VERSION 5.8 ;
BUSBITCHARS "[]" ;
DIVIDERCHAR "/" ;

# Macros-only LEF, layered on the tech that sequnmap_basic.lef creates.
# Load with loadLibaryLef(tech, ...) AFTER the basic pair; LAYER met1 and
# SITE core come from that tech.

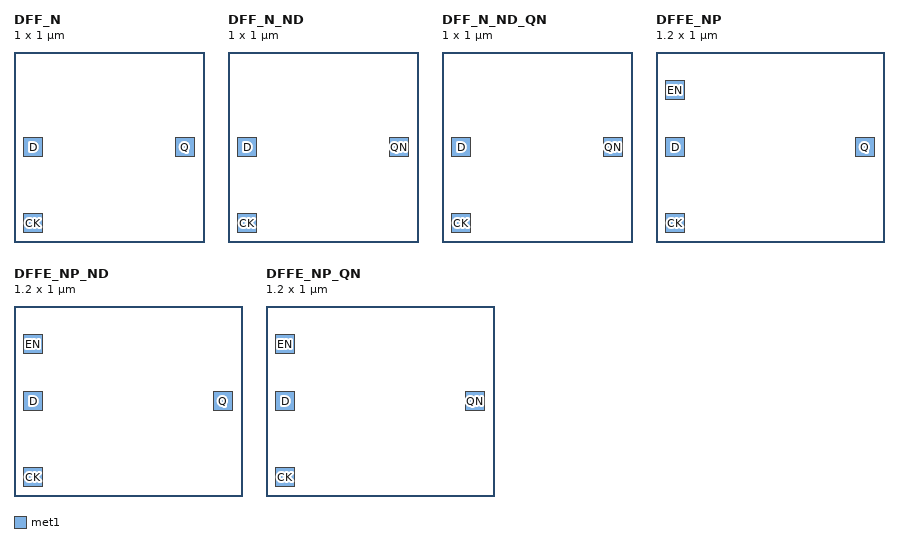
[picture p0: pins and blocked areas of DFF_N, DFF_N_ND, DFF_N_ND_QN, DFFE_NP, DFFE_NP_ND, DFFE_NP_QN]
MACRO DFF_N
  CLASS CORE ;
  ORIGIN 0 0 ;
  SIZE 1.0 BY 1.0 ;
  SITE core ;
  PIN D
    DIRECTION INPUT ;
    USE SIGNAL ;
    PORT
      LAYER met1 ;
      RECT 0.05 0.45 0.15 0.55 ;
    END
  END D
  PIN CK
    DIRECTION INPUT ;
    USE CLOCK ;
    PORT
      LAYER met1 ;
      RECT 0.05 0.05 0.15 0.15 ;
    END
  END CK
  PIN Q
    DIRECTION OUTPUT ;
    USE SIGNAL ;
    PORT
      LAYER met1 ;
      RECT 0.85 0.45 0.95 0.55 ;
    END
  END Q
END DFF_N

MACRO DFF_N_ND
  CLASS CORE ;
  ORIGIN 0 0 ;
  SIZE 1.0 BY 1.0 ;
  SITE core ;
  PIN D
    DIRECTION INPUT ;
    USE SIGNAL ;
    PORT
      LAYER met1 ;
      RECT 0.05 0.45 0.15 0.55 ;
    END
  END D
  PIN CK
    DIRECTION INPUT ;
    USE CLOCK ;
    PORT
      LAYER met1 ;
      RECT 0.05 0.05 0.15 0.15 ;
    END
  END CK
  PIN QN
    DIRECTION OUTPUT ;
    USE SIGNAL ;
    PORT
      LAYER met1 ;
      RECT 0.85 0.45 0.95 0.55 ;
    END
  END QN
END DFF_N_ND

MACRO DFF_N_ND_QN
  CLASS CORE ;
  ORIGIN 0 0 ;
  SIZE 1.0 BY 1.0 ;
  SITE core ;
  PIN D
    DIRECTION INPUT ;
    USE SIGNAL ;
    PORT
      LAYER met1 ;
      RECT 0.05 0.45 0.15 0.55 ;
    END
  END D
  PIN CK
    DIRECTION INPUT ;
    USE CLOCK ;
    PORT
      LAYER met1 ;
      RECT 0.05 0.05 0.15 0.15 ;
    END
  END CK
  PIN QN
    DIRECTION OUTPUT ;
    USE SIGNAL ;
    PORT
      LAYER met1 ;
      RECT 0.85 0.45 0.95 0.55 ;
    END
  END QN
END DFF_N_ND_QN

MACRO DFFE_NP
  CLASS CORE ;
  ORIGIN 0 0 ;
  SIZE 1.2 BY 1.0 ;
  SITE core ;
  PIN D
    DIRECTION INPUT ;
    USE SIGNAL ;
    PORT
      LAYER met1 ;
      RECT 0.05 0.45 0.15 0.55 ;
    END
  END D
  PIN EN
    DIRECTION INPUT ;
    USE SIGNAL ;
    PORT
      LAYER met1 ;
      RECT 0.05 0.75 0.15 0.85 ;
    END
  END EN
  PIN CK
    DIRECTION INPUT ;
    USE CLOCK ;
    PORT
      LAYER met1 ;
      RECT 0.05 0.05 0.15 0.15 ;
    END
  END CK
  PIN Q
    DIRECTION OUTPUT ;
    USE SIGNAL ;
    PORT
      LAYER met1 ;
      RECT 1.05 0.45 1.15 0.55 ;
    END
  END Q
END DFFE_NP

MACRO DFFE_NP_ND
  CLASS CORE ;
  ORIGIN 0 0 ;
  SIZE 1.2 BY 1.0 ;
  SITE core ;
  PIN D
    DIRECTION INPUT ;
    USE SIGNAL ;
    PORT
      LAYER met1 ;
      RECT 0.05 0.45 0.15 0.55 ;
    END
  END D
  PIN EN
    DIRECTION INPUT ;
    USE SIGNAL ;
    PORT
      LAYER met1 ;
      RECT 0.05 0.75 0.15 0.85 ;
    END
  END EN
  PIN CK
    DIRECTION INPUT ;
    USE CLOCK ;
    PORT
      LAYER met1 ;
      RECT 0.05 0.05 0.15 0.15 ;
    END
  END CK
  PIN Q
    DIRECTION OUTPUT ;
    USE SIGNAL ;
    PORT
      LAYER met1 ;
      RECT 1.05 0.45 1.15 0.55 ;
    END
  END Q
END DFFE_NP_ND

MACRO DFFE_NP_QN
  CLASS CORE ;
  ORIGIN 0 0 ;
  SIZE 1.2 BY 1.0 ;
  SITE core ;
  PIN D
    DIRECTION INPUT ;
    USE SIGNAL ;
    PORT
      LAYER met1 ;
      RECT 0.05 0.45 0.15 0.55 ;
    END
  END D
  PIN EN
    DIRECTION INPUT ;
    USE SIGNAL ;
    PORT
      LAYER met1 ;
      RECT 0.05 0.75 0.15 0.85 ;
    END
  END EN
  PIN CK
    DIRECTION INPUT ;
    USE CLOCK ;
    PORT
      LAYER met1 ;
      RECT 0.05 0.05 0.15 0.15 ;
    END
  END CK
  PIN QN
    DIRECTION OUTPUT ;
    USE SIGNAL ;
    PORT
      LAYER met1 ;
      RECT 1.05 0.45 1.15 0.55 ;
    END
  END QN
END DFFE_NP_QN

END LIBRARY
